# Generated by FakeRAM 2.0
VERSION 5.7 ;
BUSBITCHARS "[]" ;
PROPERTYDEFINITIONS
  MACRO width INTEGER ;
  MACRO depth INTEGER ;
  MACRO banks INTEGER ;
END PROPERTYDEFINITIONS
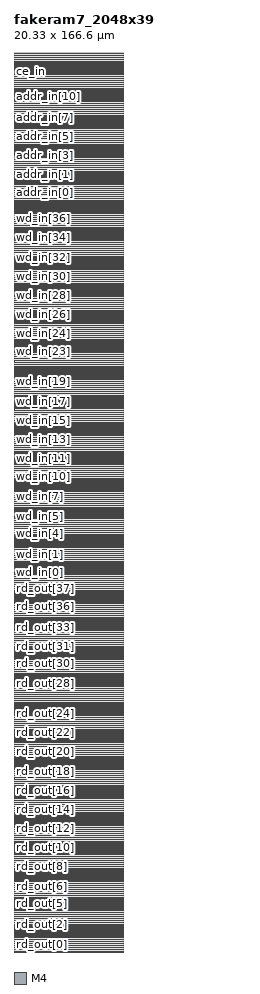
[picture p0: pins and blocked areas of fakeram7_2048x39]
MACRO fakeram7_2048x39
  PROPERTY width 39 ;
  PROPERTY depth 2048 ;
  PROPERTY banks 4 ;
  FOREIGN fakeram7_2048x39 0 0 ;
  SYMMETRY X Y R90 ;
  SIZE 20.330 BY 166.600 ;
  CLASS BLOCK ;
  PIN rd_out[0]
    DIRECTION OUTPUT ;
    USE SIGNAL ;
    SHAPE ABUTMENT ;
    PORT
      LAYER M4 ;
      RECT 0.000 0.048 0.024 0.072 ;
    END
  END rd_out[0]
  PIN rd_out[1]
    DIRECTION OUTPUT ;
    USE SIGNAL ;
    SHAPE ABUTMENT ;
    PORT
      LAYER M4 ;
      RECT 0.000 1.824 0.024 1.848 ;
    END
  END rd_out[1]
  PIN rd_out[2]
    DIRECTION OUTPUT ;
    USE SIGNAL ;
    SHAPE ABUTMENT ;
    PORT
      LAYER M4 ;
      RECT 0.000 3.600 0.024 3.624 ;
    END
  END rd_out[2]
  PIN rd_out[3]
    DIRECTION OUTPUT ;
    USE SIGNAL ;
    SHAPE ABUTMENT ;
    PORT
      LAYER M4 ;
      RECT 0.000 5.376 0.024 5.400 ;
    END
  END rd_out[3]
  PIN rd_out[4]
    DIRECTION OUTPUT ;
    USE SIGNAL ;
    SHAPE ABUTMENT ;
    PORT
      LAYER M4 ;
      RECT 0.000 7.152 0.024 7.176 ;
    END
  END rd_out[4]
  PIN rd_out[5]
    DIRECTION OUTPUT ;
    USE SIGNAL ;
    SHAPE ABUTMENT ;
    PORT
      LAYER M4 ;
      RECT 0.000 8.928 0.024 8.952 ;
    END
  END rd_out[5]
  PIN rd_out[6]
    DIRECTION OUTPUT ;
    USE SIGNAL ;
    SHAPE ABUTMENT ;
    PORT
      LAYER M4 ;
      RECT 0.000 10.704 0.024 10.728 ;
    END
  END rd_out[6]
  PIN rd_out[7]
    DIRECTION OUTPUT ;
    USE SIGNAL ;
    SHAPE ABUTMENT ;
    PORT
      LAYER M4 ;
      RECT 0.000 12.480 0.024 12.504 ;
    END
  END rd_out[7]
  PIN rd_out[8]
    DIRECTION OUTPUT ;
    USE SIGNAL ;
    SHAPE ABUTMENT ;
    PORT
      LAYER M4 ;
      RECT 0.000 14.256 0.024 14.280 ;
    END
  END rd_out[8]
  PIN rd_out[9]
    DIRECTION OUTPUT ;
    USE SIGNAL ;
    SHAPE ABUTMENT ;
    PORT
      LAYER M4 ;
      RECT 0.000 16.032 0.024 16.056 ;
    END
  END rd_out[9]
  PIN rd_out[10]
    DIRECTION OUTPUT ;
    USE SIGNAL ;
    SHAPE ABUTMENT ;
    PORT
      LAYER M4 ;
      RECT 0.000 17.808 0.024 17.832 ;
    END
  END rd_out[10]
  PIN rd_out[11]
    DIRECTION OUTPUT ;
    USE SIGNAL ;
    SHAPE ABUTMENT ;
    PORT
      LAYER M4 ;
      RECT 0.000 19.584 0.024 19.608 ;
    END
  END rd_out[11]
  PIN rd_out[12]
    DIRECTION OUTPUT ;
    USE SIGNAL ;
    SHAPE ABUTMENT ;
    PORT
      LAYER M4 ;
      RECT 0.000 21.360 0.024 21.384 ;
    END
  END rd_out[12]
  PIN rd_out[13]
    DIRECTION OUTPUT ;
    USE SIGNAL ;
    SHAPE ABUTMENT ;
    PORT
      LAYER M4 ;
      RECT 0.000 23.136 0.024 23.160 ;
    END
  END rd_out[13]
  PIN rd_out[14]
    DIRECTION OUTPUT ;
    USE SIGNAL ;
    SHAPE ABUTMENT ;
    PORT
      LAYER M4 ;
      RECT 0.000 24.912 0.024 24.936 ;
    END
  END rd_out[14]
  PIN rd_out[15]
    DIRECTION OUTPUT ;
    USE SIGNAL ;
    SHAPE ABUTMENT ;
    PORT
      LAYER M4 ;
      RECT 0.000 26.688 0.024 26.712 ;
    END
  END rd_out[15]
  PIN rd_out[16]
    DIRECTION OUTPUT ;
    USE SIGNAL ;
    SHAPE ABUTMENT ;
    PORT
      LAYER M4 ;
      RECT 0.000 28.464 0.024 28.488 ;
    END
  END rd_out[16]
  PIN rd_out[17]
    DIRECTION OUTPUT ;
    USE SIGNAL ;
    SHAPE ABUTMENT ;
    PORT
      LAYER M4 ;
      RECT 0.000 30.240 0.024 30.264 ;
    END
  END rd_out[17]
  PIN rd_out[18]
    DIRECTION OUTPUT ;
    USE SIGNAL ;
    SHAPE ABUTMENT ;
    PORT
      LAYER M4 ;
      RECT 0.000 32.016 0.024 32.040 ;
    END
  END rd_out[18]
  PIN rd_out[19]
    DIRECTION OUTPUT ;
    USE SIGNAL ;
    SHAPE ABUTMENT ;
    PORT
      LAYER M4 ;
      RECT 0.000 33.792 0.024 33.816 ;
    END
  END rd_out[19]
  PIN rd_out[20]
    DIRECTION OUTPUT ;
    USE SIGNAL ;
    SHAPE ABUTMENT ;
    PORT
      LAYER M4 ;
      RECT 0.000 35.568 0.024 35.592 ;
    END
  END rd_out[20]
  PIN rd_out[21]
    DIRECTION OUTPUT ;
    USE SIGNAL ;
    SHAPE ABUTMENT ;
    PORT
      LAYER M4 ;
      RECT 0.000 37.344 0.024 37.368 ;
    END
  END rd_out[21]
  PIN rd_out[22]
    DIRECTION OUTPUT ;
    USE SIGNAL ;
    SHAPE ABUTMENT ;
    PORT
      LAYER M4 ;
      RECT 0.000 39.120 0.024 39.144 ;
    END
  END rd_out[22]
  PIN rd_out[23]
    DIRECTION OUTPUT ;
    USE SIGNAL ;
    SHAPE ABUTMENT ;
    PORT
      LAYER M4 ;
      RECT 0.000 40.896 0.024 40.920 ;
    END
  END rd_out[23]
  PIN rd_out[24]
    DIRECTION OUTPUT ;
    USE SIGNAL ;
    SHAPE ABUTMENT ;
    PORT
      LAYER M4 ;
      RECT 0.000 42.672 0.024 42.696 ;
    END
  END rd_out[24]
  PIN rd_out[25]
    DIRECTION OUTPUT ;
    USE SIGNAL ;
    SHAPE ABUTMENT ;
    PORT
      LAYER M4 ;
      RECT 0.000 44.448 0.024 44.472 ;
    END
  END rd_out[25]
  PIN rd_out[26]
    DIRECTION OUTPUT ;
    USE SIGNAL ;
    SHAPE ABUTMENT ;
    PORT
      LAYER M4 ;
      RECT 0.000 46.224 0.024 46.248 ;
    END
  END rd_out[26]
  PIN rd_out[27]
    DIRECTION OUTPUT ;
    USE SIGNAL ;
    SHAPE ABUTMENT ;
    PORT
      LAYER M4 ;
      RECT 0.000 48.000 0.024 48.024 ;
    END
  END rd_out[27]
  PIN rd_out[28]
    DIRECTION OUTPUT ;
    USE SIGNAL ;
    SHAPE ABUTMENT ;
    PORT
      LAYER M4 ;
      RECT 0.000 49.776 0.024 49.800 ;
    END
  END rd_out[28]
  PIN rd_out[29]
    DIRECTION OUTPUT ;
    USE SIGNAL ;
    SHAPE ABUTMENT ;
    PORT
      LAYER M4 ;
      RECT 0.000 51.552 0.024 51.576 ;
    END
  END rd_out[29]
  PIN rd_out[30]
    DIRECTION OUTPUT ;
    USE SIGNAL ;
    SHAPE ABUTMENT ;
    PORT
      LAYER M4 ;
      RECT 0.000 53.328 0.024 53.352 ;
    END
  END rd_out[30]
  PIN rd_out[31]
    DIRECTION OUTPUT ;
    USE SIGNAL ;
    SHAPE ABUTMENT ;
    PORT
      LAYER M4 ;
      RECT 0.000 55.104 0.024 55.128 ;
    END
  END rd_out[31]
  PIN rd_out[32]
    DIRECTION OUTPUT ;
    USE SIGNAL ;
    SHAPE ABUTMENT ;
    PORT
      LAYER M4 ;
      RECT 0.000 56.880 0.024 56.904 ;
    END
  END rd_out[32]
  PIN rd_out[33]
    DIRECTION OUTPUT ;
    USE SIGNAL ;
    SHAPE ABUTMENT ;
    PORT
      LAYER M4 ;
      RECT 0.000 58.656 0.024 58.680 ;
    END
  END rd_out[33]
  PIN rd_out[34]
    DIRECTION OUTPUT ;
    USE SIGNAL ;
    SHAPE ABUTMENT ;
    PORT
      LAYER M4 ;
      RECT 0.000 60.432 0.024 60.456 ;
    END
  END rd_out[34]
  PIN rd_out[35]
    DIRECTION OUTPUT ;
    USE SIGNAL ;
    SHAPE ABUTMENT ;
    PORT
      LAYER M4 ;
      RECT 0.000 62.208 0.024 62.232 ;
    END
  END rd_out[35]
  PIN rd_out[36]
    DIRECTION OUTPUT ;
    USE SIGNAL ;
    SHAPE ABUTMENT ;
    PORT
      LAYER M4 ;
      RECT 0.000 63.984 0.024 64.008 ;
    END
  END rd_out[36]
  PIN rd_out[37]
    DIRECTION OUTPUT ;
    USE SIGNAL ;
    SHAPE ABUTMENT ;
    PORT
      LAYER M4 ;
      RECT 0.000 65.760 0.024 65.784 ;
    END
  END rd_out[37]
  PIN rd_out[38]
    DIRECTION OUTPUT ;
    USE SIGNAL ;
    SHAPE ABUTMENT ;
    PORT
      LAYER M4 ;
      RECT 0.000 67.536 0.024 67.560 ;
    END
  END rd_out[38]
  PIN wd_in[0]
    DIRECTION INPUT ;
    USE SIGNAL ;
    SHAPE ABUTMENT ;
    PORT
      LAYER M4 ;
      RECT 0.000 70.320 0.024 70.344 ;
    END
  END wd_in[0]
  PIN wd_in[1]
    DIRECTION INPUT ;
    USE SIGNAL ;
    SHAPE ABUTMENT ;
    PORT
      LAYER M4 ;
      RECT 0.000 72.096 0.024 72.120 ;
    END
  END wd_in[1]
  PIN wd_in[2]
    DIRECTION INPUT ;
    USE SIGNAL ;
    SHAPE ABUTMENT ;
    PORT
      LAYER M4 ;
      RECT 0.000 73.872 0.024 73.896 ;
    END
  END wd_in[2]
  PIN wd_in[3]
    DIRECTION INPUT ;
    USE SIGNAL ;
    SHAPE ABUTMENT ;
    PORT
      LAYER M4 ;
      RECT 0.000 75.648 0.024 75.672 ;
    END
  END wd_in[3]
  PIN wd_in[4]
    DIRECTION INPUT ;
    USE SIGNAL ;
    SHAPE ABUTMENT ;
    PORT
      LAYER M4 ;
      RECT 0.000 77.424 0.024 77.448 ;
    END
  END wd_in[4]
  PIN wd_in[5]
    DIRECTION INPUT ;
    USE SIGNAL ;
    SHAPE ABUTMENT ;
    PORT
      LAYER M4 ;
      RECT 0.000 79.200 0.024 79.224 ;
    END
  END wd_in[5]
  PIN wd_in[6]
    DIRECTION INPUT ;
    USE SIGNAL ;
    SHAPE ABUTMENT ;
    PORT
      LAYER M4 ;
      RECT 0.000 80.976 0.024 81.000 ;
    END
  END wd_in[6]
  PIN wd_in[7]
    DIRECTION INPUT ;
    USE SIGNAL ;
    SHAPE ABUTMENT ;
    PORT
      LAYER M4 ;
      RECT 0.000 82.752 0.024 82.776 ;
    END
  END wd_in[7]
  PIN wd_in[8]
    DIRECTION INPUT ;
    USE SIGNAL ;
    SHAPE ABUTMENT ;
    PORT
      LAYER M4 ;
      RECT 0.000 84.528 0.024 84.552 ;
    END
  END wd_in[8]
  PIN wd_in[9]
    DIRECTION INPUT ;
    USE SIGNAL ;
    SHAPE ABUTMENT ;
    PORT
      LAYER M4 ;
      RECT 0.000 86.304 0.024 86.328 ;
    END
  END wd_in[9]
  PIN wd_in[10]
    DIRECTION INPUT ;
    USE SIGNAL ;
    SHAPE ABUTMENT ;
    PORT
      LAYER M4 ;
      RECT 0.000 88.080 0.024 88.104 ;
    END
  END wd_in[10]
  PIN wd_in[11]
    DIRECTION INPUT ;
    USE SIGNAL ;
    SHAPE ABUTMENT ;
    PORT
      LAYER M4 ;
      RECT 0.000 89.856 0.024 89.880 ;
    END
  END wd_in[11]
  PIN wd_in[12]
    DIRECTION INPUT ;
    USE SIGNAL ;
    SHAPE ABUTMENT ;
    PORT
      LAYER M4 ;
      RECT 0.000 91.632 0.024 91.656 ;
    END
  END wd_in[12]
  PIN wd_in[13]
    DIRECTION INPUT ;
    USE SIGNAL ;
    SHAPE ABUTMENT ;
    PORT
      LAYER M4 ;
      RECT 0.000 93.408 0.024 93.432 ;
    END
  END wd_in[13]
  PIN wd_in[14]
    DIRECTION INPUT ;
    USE SIGNAL ;
    SHAPE ABUTMENT ;
    PORT
      LAYER M4 ;
      RECT 0.000 95.184 0.024 95.208 ;
    END
  END wd_in[14]
  PIN wd_in[15]
    DIRECTION INPUT ;
    USE SIGNAL ;
    SHAPE ABUTMENT ;
    PORT
      LAYER M4 ;
      RECT 0.000 96.960 0.024 96.984 ;
    END
  END wd_in[15]
  PIN wd_in[16]
    DIRECTION INPUT ;
    USE SIGNAL ;
    SHAPE ABUTMENT ;
    PORT
      LAYER M4 ;
      RECT 0.000 98.736 0.024 98.760 ;
    END
  END wd_in[16]
  PIN wd_in[17]
    DIRECTION INPUT ;
    USE SIGNAL ;
    SHAPE ABUTMENT ;
    PORT
      LAYER M4 ;
      RECT 0.000 100.512 0.024 100.536 ;
    END
  END wd_in[17]
  PIN wd_in[18]
    DIRECTION INPUT ;
    USE SIGNAL ;
    SHAPE ABUTMENT ;
    PORT
      LAYER M4 ;
      RECT 0.000 102.288 0.024 102.312 ;
    END
  END wd_in[18]
  PIN wd_in[19]
    DIRECTION INPUT ;
    USE SIGNAL ;
    SHAPE ABUTMENT ;
    PORT
      LAYER M4 ;
      RECT 0.000 104.064 0.024 104.088 ;
    END
  END wd_in[19]
  PIN wd_in[20]
    DIRECTION INPUT ;
    USE SIGNAL ;
    SHAPE ABUTMENT ;
    PORT
      LAYER M4 ;
      RECT 0.000 105.840 0.024 105.864 ;
    END
  END wd_in[20]
  PIN wd_in[21]
    DIRECTION INPUT ;
    USE SIGNAL ;
    SHAPE ABUTMENT ;
    PORT
      LAYER M4 ;
      RECT 0.000 107.616 0.024 107.640 ;
    END
  END wd_in[21]
  PIN wd_in[22]
    DIRECTION INPUT ;
    USE SIGNAL ;
    SHAPE ABUTMENT ;
    PORT
      LAYER M4 ;
      RECT 0.000 109.392 0.024 109.416 ;
    END
  END wd_in[22]
  PIN wd_in[23]
    DIRECTION INPUT ;
    USE SIGNAL ;
    SHAPE ABUTMENT ;
    PORT
      LAYER M4 ;
      RECT 0.000 111.168 0.024 111.192 ;
    END
  END wd_in[23]
  PIN wd_in[24]
    DIRECTION INPUT ;
    USE SIGNAL ;
    SHAPE ABUTMENT ;
    PORT
      LAYER M4 ;
      RECT 0.000 112.944 0.024 112.968 ;
    END
  END wd_in[24]
  PIN wd_in[25]
    DIRECTION INPUT ;
    USE SIGNAL ;
    SHAPE ABUTMENT ;
    PORT
      LAYER M4 ;
      RECT 0.000 114.720 0.024 114.744 ;
    END
  END wd_in[25]
  PIN wd_in[26]
    DIRECTION INPUT ;
    USE SIGNAL ;
    SHAPE ABUTMENT ;
    PORT
      LAYER M4 ;
      RECT 0.000 116.496 0.024 116.520 ;
    END
  END wd_in[26]
  PIN wd_in[27]
    DIRECTION INPUT ;
    USE SIGNAL ;
    SHAPE ABUTMENT ;
    PORT
      LAYER M4 ;
      RECT 0.000 118.272 0.024 118.296 ;
    END
  END wd_in[27]
  PIN wd_in[28]
    DIRECTION INPUT ;
    USE SIGNAL ;
    SHAPE ABUTMENT ;
    PORT
      LAYER M4 ;
      RECT 0.000 120.048 0.024 120.072 ;
    END
  END wd_in[28]
  PIN wd_in[29]
    DIRECTION INPUT ;
    USE SIGNAL ;
    SHAPE ABUTMENT ;
    PORT
      LAYER M4 ;
      RECT 0.000 121.824 0.024 121.848 ;
    END
  END wd_in[29]
  PIN wd_in[30]
    DIRECTION INPUT ;
    USE SIGNAL ;
    SHAPE ABUTMENT ;
    PORT
      LAYER M4 ;
      RECT 0.000 123.600 0.024 123.624 ;
    END
  END wd_in[30]
  PIN wd_in[31]
    DIRECTION INPUT ;
    USE SIGNAL ;
    SHAPE ABUTMENT ;
    PORT
      LAYER M4 ;
      RECT 0.000 125.376 0.024 125.400 ;
    END
  END wd_in[31]
  PIN wd_in[32]
    DIRECTION INPUT ;
    USE SIGNAL ;
    SHAPE ABUTMENT ;
    PORT
      LAYER M4 ;
      RECT 0.000 127.152 0.024 127.176 ;
    END
  END wd_in[32]
  PIN wd_in[33]
    DIRECTION INPUT ;
    USE SIGNAL ;
    SHAPE ABUTMENT ;
    PORT
      LAYER M4 ;
      RECT 0.000 128.928 0.024 128.952 ;
    END
  END wd_in[33]
  PIN wd_in[34]
    DIRECTION INPUT ;
    USE SIGNAL ;
    SHAPE ABUTMENT ;
    PORT
      LAYER M4 ;
      RECT 0.000 130.704 0.024 130.728 ;
    END
  END wd_in[34]
  PIN wd_in[35]
    DIRECTION INPUT ;
    USE SIGNAL ;
    SHAPE ABUTMENT ;
    PORT
      LAYER M4 ;
      RECT 0.000 132.480 0.024 132.504 ;
    END
  END wd_in[35]
  PIN wd_in[36]
    DIRECTION INPUT ;
    USE SIGNAL ;
    SHAPE ABUTMENT ;
    PORT
      LAYER M4 ;
      RECT 0.000 134.256 0.024 134.280 ;
    END
  END wd_in[36]
  PIN wd_in[37]
    DIRECTION INPUT ;
    USE SIGNAL ;
    SHAPE ABUTMENT ;
    PORT
      LAYER M4 ;
      RECT 0.000 136.032 0.024 136.056 ;
    END
  END wd_in[37]
  PIN wd_in[38]
    DIRECTION INPUT ;
    USE SIGNAL ;
    SHAPE ABUTMENT ;
    PORT
      LAYER M4 ;
      RECT 0.000 137.808 0.024 137.832 ;
    END
  END wd_in[38]
  PIN addr_in[0]
    DIRECTION INPUT ;
    USE SIGNAL ;
    SHAPE ABUTMENT ;
    PORT
      LAYER M4 ;
      RECT 0.000 140.592 0.024 140.616 ;
    END
  END addr_in[0]
  PIN addr_in[1]
    DIRECTION INPUT ;
    USE SIGNAL ;
    SHAPE ABUTMENT ;
    PORT
      LAYER M4 ;
      RECT 0.000 142.368 0.024 142.392 ;
    END
  END addr_in[1]
  PIN addr_in[2]
    DIRECTION INPUT ;
    USE SIGNAL ;
    SHAPE ABUTMENT ;
    PORT
      LAYER M4 ;
      RECT 0.000 144.144 0.024 144.168 ;
    END
  END addr_in[2]
  PIN addr_in[3]
    DIRECTION INPUT ;
    USE SIGNAL ;
    SHAPE ABUTMENT ;
    PORT
      LAYER M4 ;
      RECT 0.000 145.920 0.024 145.944 ;
    END
  END addr_in[3]
  PIN addr_in[4]
    DIRECTION INPUT ;
    USE SIGNAL ;
    SHAPE ABUTMENT ;
    PORT
      LAYER M4 ;
      RECT 0.000 147.696 0.024 147.720 ;
    END
  END addr_in[4]
  PIN addr_in[5]
    DIRECTION INPUT ;
    USE SIGNAL ;
    SHAPE ABUTMENT ;
    PORT
      LAYER M4 ;
      RECT 0.000 149.472 0.024 149.496 ;
    END
  END addr_in[5]
  PIN addr_in[6]
    DIRECTION INPUT ;
    USE SIGNAL ;
    SHAPE ABUTMENT ;
    PORT
      LAYER M4 ;
      RECT 0.000 151.248 0.024 151.272 ;
    END
  END addr_in[6]
  PIN addr_in[7]
    DIRECTION INPUT ;
    USE SIGNAL ;
    SHAPE ABUTMENT ;
    PORT
      LAYER M4 ;
      RECT 0.000 153.024 0.024 153.048 ;
    END
  END addr_in[7]
  PIN addr_in[8]
    DIRECTION INPUT ;
    USE SIGNAL ;
    SHAPE ABUTMENT ;
    PORT
      LAYER M4 ;
      RECT 0.000 154.800 0.024 154.824 ;
    END
  END addr_in[8]
  PIN addr_in[9]
    DIRECTION INPUT ;
    USE SIGNAL ;
    SHAPE ABUTMENT ;
    PORT
      LAYER M4 ;
      RECT 0.000 156.576 0.024 156.600 ;
    END
  END addr_in[9]
  PIN addr_in[10]
    DIRECTION INPUT ;
    USE SIGNAL ;
    SHAPE ABUTMENT ;
    PORT
      LAYER M4 ;
      RECT 0.000 158.352 0.024 158.376 ;
    END
  END addr_in[10]
  PIN we_in
    DIRECTION INPUT ;
    USE SIGNAL ;
    SHAPE ABUTMENT ;
    PORT
      LAYER M4 ;
      RECT 0.000 161.136 0.024 161.160 ;
    END
  END we_in
  PIN ce_in
    DIRECTION INPUT ;
    USE SIGNAL ;
    SHAPE ABUTMENT ;
    PORT
      LAYER M4 ;
      RECT 0.000 162.912 0.024 162.936 ;
    END
  END ce_in
  PIN clk
    DIRECTION INPUT ;
    USE SIGNAL ;
    SHAPE ABUTMENT ;
    PORT
      LAYER M4 ;
      RECT 0.000 164.688 0.024 164.712 ;
    END
  END clk
  PIN VSS
    DIRECTION INOUT ;
    USE GROUND ;
    PORT
      LAYER M4 ;
      RECT 0.048 0.000 20.282 0.096 ;
      RECT 0.048 0.768 20.282 0.864 ;
      RECT 0.048 1.536 20.282 1.632 ;
      RECT 0.048 2.304 20.282 2.400 ;
      RECT 0.048 3.072 20.282 3.168 ;
      RECT 0.048 3.840 20.282 3.936 ;
      RECT 0.048 4.608 20.282 4.704 ;
      RECT 0.048 5.376 20.282 5.472 ;
      RECT 0.048 6.144 20.282 6.240 ;
      RECT 0.048 6.912 20.282 7.008 ;
      RECT 0.048 7.680 20.282 7.776 ;
      RECT 0.048 8.448 20.282 8.544 ;
      RECT 0.048 9.216 20.282 9.312 ;
      RECT 0.048 9.984 20.282 10.080 ;
      RECT 0.048 10.752 20.282 10.848 ;
      RECT 0.048 11.520 20.282 11.616 ;
      RECT 0.048 12.288 20.282 12.384 ;
      RECT 0.048 13.056 20.282 13.152 ;
      RECT 0.048 13.824 20.282 13.920 ;
      RECT 0.048 14.592 20.282 14.688 ;
      RECT 0.048 15.360 20.282 15.456 ;
      RECT 0.048 16.128 20.282 16.224 ;
      RECT 0.048 16.896 20.282 16.992 ;
      RECT 0.048 17.664 20.282 17.760 ;
      RECT 0.048 18.432 20.282 18.528 ;
      RECT 0.048 19.200 20.282 19.296 ;
      RECT 0.048 19.968 20.282 20.064 ;
      RECT 0.048 20.736 20.282 20.832 ;
      RECT 0.048 21.504 20.282 21.600 ;
      RECT 0.048 22.272 20.282 22.368 ;
      RECT 0.048 23.040 20.282 23.136 ;
      RECT 0.048 23.808 20.282 23.904 ;
      RECT 0.048 24.576 20.282 24.672 ;
      RECT 0.048 25.344 20.282 25.440 ;
      RECT 0.048 26.112 20.282 26.208 ;
      RECT 0.048 26.880 20.282 26.976 ;
      RECT 0.048 27.648 20.282 27.744 ;
      RECT 0.048 28.416 20.282 28.512 ;
      RECT 0.048 29.184 20.282 29.280 ;
      RECT 0.048 29.952 20.282 30.048 ;
      RECT 0.048 30.720 20.282 30.816 ;
      RECT 0.048 31.488 20.282 31.584 ;
      RECT 0.048 32.256 20.282 32.352 ;
      RECT 0.048 33.024 20.282 33.120 ;
      RECT 0.048 33.792 20.282 33.888 ;
      RECT 0.048 34.560 20.282 34.656 ;
      RECT 0.048 35.328 20.282 35.424 ;
      RECT 0.048 36.096 20.282 36.192 ;
      RECT 0.048 36.864 20.282 36.960 ;
      RECT 0.048 37.632 20.282 37.728 ;
      RECT 0.048 38.400 20.282 38.496 ;
      RECT 0.048 39.168 20.282 39.264 ;
      RECT 0.048 39.936 20.282 40.032 ;
      RECT 0.048 40.704 20.282 40.800 ;
      RECT 0.048 41.472 20.282 41.568 ;
      RECT 0.048 42.240 20.282 42.336 ;
      RECT 0.048 43.008 20.282 43.104 ;
      RECT 0.048 43.776 20.282 43.872 ;
      RECT 0.048 44.544 20.282 44.640 ;
      RECT 0.048 45.312 20.282 45.408 ;
      RECT 0.048 46.080 20.282 46.176 ;
      RECT 0.048 46.848 20.282 46.944 ;
      RECT 0.048 47.616 20.282 47.712 ;
      RECT 0.048 48.384 20.282 48.480 ;
      RECT 0.048 49.152 20.282 49.248 ;
      RECT 0.048 49.920 20.282 50.016 ;
      RECT 0.048 50.688 20.282 50.784 ;
      RECT 0.048 51.456 20.282 51.552 ;
      RECT 0.048 52.224 20.282 52.320 ;
      RECT 0.048 52.992 20.282 53.088 ;
      RECT 0.048 53.760 20.282 53.856 ;
      RECT 0.048 54.528 20.282 54.624 ;
      RECT 0.048 55.296 20.282 55.392 ;
      RECT 0.048 56.064 20.282 56.160 ;
      RECT 0.048 56.832 20.282 56.928 ;
      RECT 0.048 57.600 20.282 57.696 ;
      RECT 0.048 58.368 20.282 58.464 ;
      RECT 0.048 59.136 20.282 59.232 ;
      RECT 0.048 59.904 20.282 60.000 ;
      RECT 0.048 60.672 20.282 60.768 ;
      RECT 0.048 61.440 20.282 61.536 ;
      RECT 0.048 62.208 20.282 62.304 ;
      RECT 0.048 62.976 20.282 63.072 ;
      RECT 0.048 63.744 20.282 63.840 ;
      RECT 0.048 64.512 20.282 64.608 ;
      RECT 0.048 65.280 20.282 65.376 ;
      RECT 0.048 66.048 20.282 66.144 ;
      RECT 0.048 66.816 20.282 66.912 ;
      RECT 0.048 67.584 20.282 67.680 ;
      RECT 0.048 68.352 20.282 68.448 ;
      RECT 0.048 69.120 20.282 69.216 ;
      RECT 0.048 69.888 20.282 69.984 ;
      RECT 0.048 70.656 20.282 70.752 ;
      RECT 0.048 71.424 20.282 71.520 ;
      RECT 0.048 72.192 20.282 72.288 ;
      RECT 0.048 72.960 20.282 73.056 ;
      RECT 0.048 73.728 20.282 73.824 ;
      RECT 0.048 74.496 20.282 74.592 ;
      RECT 0.048 75.264 20.282 75.360 ;
      RECT 0.048 76.032 20.282 76.128 ;
      RECT 0.048 76.800 20.282 76.896 ;
      RECT 0.048 77.568 20.282 77.664 ;
      RECT 0.048 78.336 20.282 78.432 ;
      RECT 0.048 79.104 20.282 79.200 ;
      RECT 0.048 79.872 20.282 79.968 ;
      RECT 0.048 80.640 20.282 80.736 ;
      RECT 0.048 81.408 20.282 81.504 ;
      RECT 0.048 82.176 20.282 82.272 ;
      RECT 0.048 82.944 20.282 83.040 ;
      RECT 0.048 83.712 20.282 83.808 ;
      RECT 0.048 84.480 20.282 84.576 ;
      RECT 0.048 85.248 20.282 85.344 ;
      RECT 0.048 86.016 20.282 86.112 ;
      RECT 0.048 86.784 20.282 86.880 ;
      RECT 0.048 87.552 20.282 87.648 ;
      RECT 0.048 88.320 20.282 88.416 ;
      RECT 0.048 89.088 20.282 89.184 ;
      RECT 0.048 89.856 20.282 89.952 ;
      RECT 0.048 90.624 20.282 90.720 ;
      RECT 0.048 91.392 20.282 91.488 ;
      RECT 0.048 92.160 20.282 92.256 ;
      RECT 0.048 92.928 20.282 93.024 ;
      RECT 0.048 93.696 20.282 93.792 ;
      RECT 0.048 94.464 20.282 94.560 ;
      RECT 0.048 95.232 20.282 95.328 ;
      RECT 0.048 96.000 20.282 96.096 ;
      RECT 0.048 96.768 20.282 96.864 ;
      RECT 0.048 97.536 20.282 97.632 ;
      RECT 0.048 98.304 20.282 98.400 ;
      RECT 0.048 99.072 20.282 99.168 ;
      RECT 0.048 99.840 20.282 99.936 ;
      RECT 0.048 100.608 20.282 100.704 ;
      RECT 0.048 101.376 20.282 101.472 ;
      RECT 0.048 102.144 20.282 102.240 ;
      RECT 0.048 102.912 20.282 103.008 ;
      RECT 0.048 103.680 20.282 103.776 ;
      RECT 0.048 104.448 20.282 104.544 ;
      RECT 0.048 105.216 20.282 105.312 ;
      RECT 0.048 105.984 20.282 106.080 ;
      RECT 0.048 106.752 20.282 106.848 ;
      RECT 0.048 107.520 20.282 107.616 ;
      RECT 0.048 108.288 20.282 108.384 ;
      RECT 0.048 109.056 20.282 109.152 ;
      RECT 0.048 109.824 20.282 109.920 ;
      RECT 0.048 110.592 20.282 110.688 ;
      RECT 0.048 111.360 20.282 111.456 ;
      RECT 0.048 112.128 20.282 112.224 ;
      RECT 0.048 112.896 20.282 112.992 ;
      RECT 0.048 113.664 20.282 113.760 ;
      RECT 0.048 114.432 20.282 114.528 ;
      RECT 0.048 115.200 20.282 115.296 ;
      RECT 0.048 115.968 20.282 116.064 ;
      RECT 0.048 116.736 20.282 116.832 ;
      RECT 0.048 117.504 20.282 117.600 ;
      RECT 0.048 118.272 20.282 118.368 ;
      RECT 0.048 119.040 20.282 119.136 ;
      RECT 0.048 119.808 20.282 119.904 ;
      RECT 0.048 120.576 20.282 120.672 ;
      RECT 0.048 121.344 20.282 121.440 ;
      RECT 0.048 122.112 20.282 122.208 ;
      RECT 0.048 122.880 20.282 122.976 ;
      RECT 0.048 123.648 20.282 123.744 ;
      RECT 0.048 124.416 20.282 124.512 ;
      RECT 0.048 125.184 20.282 125.280 ;
      RECT 0.048 125.952 20.282 126.048 ;
      RECT 0.048 126.720 20.282 126.816 ;
      RECT 0.048 127.488 20.282 127.584 ;
      RECT 0.048 128.256 20.282 128.352 ;
      RECT 0.048 129.024 20.282 129.120 ;
      RECT 0.048 129.792 20.282 129.888 ;
      RECT 0.048 130.560 20.282 130.656 ;
      RECT 0.048 131.328 20.282 131.424 ;
      RECT 0.048 132.096 20.282 132.192 ;
      RECT 0.048 132.864 20.282 132.960 ;
      RECT 0.048 133.632 20.282 133.728 ;
      RECT 0.048 134.400 20.282 134.496 ;
      RECT 0.048 135.168 20.282 135.264 ;
      RECT 0.048 135.936 20.282 136.032 ;
      RECT 0.048 136.704 20.282 136.800 ;
      RECT 0.048 137.472 20.282 137.568 ;
      RECT 0.048 138.240 20.282 138.336 ;
      RECT 0.048 139.008 20.282 139.104 ;
      RECT 0.048 139.776 20.282 139.872 ;
      RECT 0.048 140.544 20.282 140.640 ;
      RECT 0.048 141.312 20.282 141.408 ;
      RECT 0.048 142.080 20.282 142.176 ;
      RECT 0.048 142.848 20.282 142.944 ;
      RECT 0.048 143.616 20.282 143.712 ;
      RECT 0.048 144.384 20.282 144.480 ;
      RECT 0.048 145.152 20.282 145.248 ;
      RECT 0.048 145.920 20.282 146.016 ;
      RECT 0.048 146.688 20.282 146.784 ;
      RECT 0.048 147.456 20.282 147.552 ;
      RECT 0.048 148.224 20.282 148.320 ;
      RECT 0.048 148.992 20.282 149.088 ;
      RECT 0.048 149.760 20.282 149.856 ;
      RECT 0.048 150.528 20.282 150.624 ;
      RECT 0.048 151.296 20.282 151.392 ;
      RECT 0.048 152.064 20.282 152.160 ;
      RECT 0.048 152.832 20.282 152.928 ;
      RECT 0.048 153.600 20.282 153.696 ;
      RECT 0.048 154.368 20.282 154.464 ;
      RECT 0.048 155.136 20.282 155.232 ;
      RECT 0.048 155.904 20.282 156.000 ;
      RECT 0.048 156.672 20.282 156.768 ;
      RECT 0.048 157.440 20.282 157.536 ;
      RECT 0.048 158.208 20.282 158.304 ;
      RECT 0.048 158.976 20.282 159.072 ;
      RECT 0.048 159.744 20.282 159.840 ;
      RECT 0.048 160.512 20.282 160.608 ;
      RECT 0.048 161.280 20.282 161.376 ;
      RECT 0.048 162.048 20.282 162.144 ;
      RECT 0.048 162.816 20.282 162.912 ;
      RECT 0.048 163.584 20.282 163.680 ;
      RECT 0.048 164.352 20.282 164.448 ;
      RECT 0.048 165.120 20.282 165.216 ;
      RECT 0.048 165.888 20.282 165.984 ;
    END
  END VSS
  PIN VDD
    DIRECTION INOUT ;
    USE POWER ;
    PORT
      LAYER M4 ;
      RECT 0.048 0.384 20.282 0.480 ;
      RECT 0.048 1.152 20.282 1.248 ;
      RECT 0.048 1.920 20.282 2.016 ;
      RECT 0.048 2.688 20.282 2.784 ;
      RECT 0.048 3.456 20.282 3.552 ;
      RECT 0.048 4.224 20.282 4.320 ;
      RECT 0.048 4.992 20.282 5.088 ;
      RECT 0.048 5.760 20.282 5.856 ;
      RECT 0.048 6.528 20.282 6.624 ;
      RECT 0.048 7.296 20.282 7.392 ;
      RECT 0.048 8.064 20.282 8.160 ;
      RECT 0.048 8.832 20.282 8.928 ;
      RECT 0.048 9.600 20.282 9.696 ;
      RECT 0.048 10.368 20.282 10.464 ;
      RECT 0.048 11.136 20.282 11.232 ;
      RECT 0.048 11.904 20.282 12.000 ;
      RECT 0.048 12.672 20.282 12.768 ;
      RECT 0.048 13.440 20.282 13.536 ;
      RECT 0.048 14.208 20.282 14.304 ;
      RECT 0.048 14.976 20.282 15.072 ;
      RECT 0.048 15.744 20.282 15.840 ;
      RECT 0.048 16.512 20.282 16.608 ;
      RECT 0.048 17.280 20.282 17.376 ;
      RECT 0.048 18.048 20.282 18.144 ;
      RECT 0.048 18.816 20.282 18.912 ;
      RECT 0.048 19.584 20.282 19.680 ;
      RECT 0.048 20.352 20.282 20.448 ;
      RECT 0.048 21.120 20.282 21.216 ;
      RECT 0.048 21.888 20.282 21.984 ;
      RECT 0.048 22.656 20.282 22.752 ;
      RECT 0.048 23.424 20.282 23.520 ;
      RECT 0.048 24.192 20.282 24.288 ;
      RECT 0.048 24.960 20.282 25.056 ;
      RECT 0.048 25.728 20.282 25.824 ;
      RECT 0.048 26.496 20.282 26.592 ;
      RECT 0.048 27.264 20.282 27.360 ;
      RECT 0.048 28.032 20.282 28.128 ;
      RECT 0.048 28.800 20.282 28.896 ;
      RECT 0.048 29.568 20.282 29.664 ;
      RECT 0.048 30.336 20.282 30.432 ;
      RECT 0.048 31.104 20.282 31.200 ;
      RECT 0.048 31.872 20.282 31.968 ;
      RECT 0.048 32.640 20.282 32.736 ;
      RECT 0.048 33.408 20.282 33.504 ;
      RECT 0.048 34.176 20.282 34.272 ;
      RECT 0.048 34.944 20.282 35.040 ;
      RECT 0.048 35.712 20.282 35.808 ;
      RECT 0.048 36.480 20.282 36.576 ;
      RECT 0.048 37.248 20.282 37.344 ;
      RECT 0.048 38.016 20.282 38.112 ;
      RECT 0.048 38.784 20.282 38.880 ;
      RECT 0.048 39.552 20.282 39.648 ;
      RECT 0.048 40.320 20.282 40.416 ;
      RECT 0.048 41.088 20.282 41.184 ;
      RECT 0.048 41.856 20.282 41.952 ;
      RECT 0.048 42.624 20.282 42.720 ;
      RECT 0.048 43.392 20.282 43.488 ;
      RECT 0.048 44.160 20.282 44.256 ;
      RECT 0.048 44.928 20.282 45.024 ;
      RECT 0.048 45.696 20.282 45.792 ;
      RECT 0.048 46.464 20.282 46.560 ;
      RECT 0.048 47.232 20.282 47.328 ;
      RECT 0.048 48.000 20.282 48.096 ;
      RECT 0.048 48.768 20.282 48.864 ;
      RECT 0.048 49.536 20.282 49.632 ;
      RECT 0.048 50.304 20.282 50.400 ;
      RECT 0.048 51.072 20.282 51.168 ;
      RECT 0.048 51.840 20.282 51.936 ;
      RECT 0.048 52.608 20.282 52.704 ;
      RECT 0.048 53.376 20.282 53.472 ;
      RECT 0.048 54.144 20.282 54.240 ;
      RECT 0.048 54.912 20.282 55.008 ;
      RECT 0.048 55.680 20.282 55.776 ;
      RECT 0.048 56.448 20.282 56.544 ;
      RECT 0.048 57.216 20.282 57.312 ;
      RECT 0.048 57.984 20.282 58.080 ;
      RECT 0.048 58.752 20.282 58.848 ;
      RECT 0.048 59.520 20.282 59.616 ;
      RECT 0.048 60.288 20.282 60.384 ;
      RECT 0.048 61.056 20.282 61.152 ;
      RECT 0.048 61.824 20.282 61.920 ;
      RECT 0.048 62.592 20.282 62.688 ;
      RECT 0.048 63.360 20.282 63.456 ;
      RECT 0.048 64.128 20.282 64.224 ;
      RECT 0.048 64.896 20.282 64.992 ;
      RECT 0.048 65.664 20.282 65.760 ;
      RECT 0.048 66.432 20.282 66.528 ;
      RECT 0.048 67.200 20.282 67.296 ;
      RECT 0.048 67.968 20.282 68.064 ;
      RECT 0.048 68.736 20.282 68.832 ;
      RECT 0.048 69.504 20.282 69.600 ;
      RECT 0.048 70.272 20.282 70.368 ;
      RECT 0.048 71.040 20.282 71.136 ;
      RECT 0.048 71.808 20.282 71.904 ;
      RECT 0.048 72.576 20.282 72.672 ;
      RECT 0.048 73.344 20.282 73.440 ;
      RECT 0.048 74.112 20.282 74.208 ;
      RECT 0.048 74.880 20.282 74.976 ;
      RECT 0.048 75.648 20.282 75.744 ;
      RECT 0.048 76.416 20.282 76.512 ;
      RECT 0.048 77.184 20.282 77.280 ;
      RECT 0.048 77.952 20.282 78.048 ;
      RECT 0.048 78.720 20.282 78.816 ;
      RECT 0.048 79.488 20.282 79.584 ;
      RECT 0.048 80.256 20.282 80.352 ;
      RECT 0.048 81.024 20.282 81.120 ;
      RECT 0.048 81.792 20.282 81.888 ;
      RECT 0.048 82.560 20.282 82.656 ;
      RECT 0.048 83.328 20.282 83.424 ;
      RECT 0.048 84.096 20.282 84.192 ;
      RECT 0.048 84.864 20.282 84.960 ;
      RECT 0.048 85.632 20.282 85.728 ;
      RECT 0.048 86.400 20.282 86.496 ;
      RECT 0.048 87.168 20.282 87.264 ;
      RECT 0.048 87.936 20.282 88.032 ;
      RECT 0.048 88.704 20.282 88.800 ;
      RECT 0.048 89.472 20.282 89.568 ;
      RECT 0.048 90.240 20.282 90.336 ;
      RECT 0.048 91.008 20.282 91.104 ;
      RECT 0.048 91.776 20.282 91.872 ;
      RECT 0.048 92.544 20.282 92.640 ;
      RECT 0.048 93.312 20.282 93.408 ;
      RECT 0.048 94.080 20.282 94.176 ;
      RECT 0.048 94.848 20.282 94.944 ;
      RECT 0.048 95.616 20.282 95.712 ;
      RECT 0.048 96.384 20.282 96.480 ;
      RECT 0.048 97.152 20.282 97.248 ;
      RECT 0.048 97.920 20.282 98.016 ;
      RECT 0.048 98.688 20.282 98.784 ;
      RECT 0.048 99.456 20.282 99.552 ;
      RECT 0.048 100.224 20.282 100.320 ;
      RECT 0.048 100.992 20.282 101.088 ;
      RECT 0.048 101.760 20.282 101.856 ;
      RECT 0.048 102.528 20.282 102.624 ;
      RECT 0.048 103.296 20.282 103.392 ;
      RECT 0.048 104.064 20.282 104.160 ;
      RECT 0.048 104.832 20.282 104.928 ;
      RECT 0.048 105.600 20.282 105.696 ;
      RECT 0.048 106.368 20.282 106.464 ;
      RECT 0.048 107.136 20.282 107.232 ;
      RECT 0.048 107.904 20.282 108.000 ;
      RECT 0.048 108.672 20.282 108.768 ;
      RECT 0.048 109.440 20.282 109.536 ;
      RECT 0.048 110.208 20.282 110.304 ;
      RECT 0.048 110.976 20.282 111.072 ;
      RECT 0.048 111.744 20.282 111.840 ;
      RECT 0.048 112.512 20.282 112.608 ;
      RECT 0.048 113.280 20.282 113.376 ;
      RECT 0.048 114.048 20.282 114.144 ;
      RECT 0.048 114.816 20.282 114.912 ;
      RECT 0.048 115.584 20.282 115.680 ;
      RECT 0.048 116.352 20.282 116.448 ;
      RECT 0.048 117.120 20.282 117.216 ;
      RECT 0.048 117.888 20.282 117.984 ;
      RECT 0.048 118.656 20.282 118.752 ;
      RECT 0.048 119.424 20.282 119.520 ;
      RECT 0.048 120.192 20.282 120.288 ;
      RECT 0.048 120.960 20.282 121.056 ;
      RECT 0.048 121.728 20.282 121.824 ;
      RECT 0.048 122.496 20.282 122.592 ;
      RECT 0.048 123.264 20.282 123.360 ;
      RECT 0.048 124.032 20.282 124.128 ;
      RECT 0.048 124.800 20.282 124.896 ;
      RECT 0.048 125.568 20.282 125.664 ;
      RECT 0.048 126.336 20.282 126.432 ;
      RECT 0.048 127.104 20.282 127.200 ;
      RECT 0.048 127.872 20.282 127.968 ;
      RECT 0.048 128.640 20.282 128.736 ;
      RECT 0.048 129.408 20.282 129.504 ;
      RECT 0.048 130.176 20.282 130.272 ;
      RECT 0.048 130.944 20.282 131.040 ;
      RECT 0.048 131.712 20.282 131.808 ;
      RECT 0.048 132.480 20.282 132.576 ;
      RECT 0.048 133.248 20.282 133.344 ;
      RECT 0.048 134.016 20.282 134.112 ;
      RECT 0.048 134.784 20.282 134.880 ;
      RECT 0.048 135.552 20.282 135.648 ;
      RECT 0.048 136.320 20.282 136.416 ;
      RECT 0.048 137.088 20.282 137.184 ;
      RECT 0.048 137.856 20.282 137.952 ;
      RECT 0.048 138.624 20.282 138.720 ;
      RECT 0.048 139.392 20.282 139.488 ;
      RECT 0.048 140.160 20.282 140.256 ;
      RECT 0.048 140.928 20.282 141.024 ;
      RECT 0.048 141.696 20.282 141.792 ;
      RECT 0.048 142.464 20.282 142.560 ;
      RECT 0.048 143.232 20.282 143.328 ;
      RECT 0.048 144.000 20.282 144.096 ;
      RECT 0.048 144.768 20.282 144.864 ;
      RECT 0.048 145.536 20.282 145.632 ;
      RECT 0.048 146.304 20.282 146.400 ;
      RECT 0.048 147.072 20.282 147.168 ;
      RECT 0.048 147.840 20.282 147.936 ;
      RECT 0.048 148.608 20.282 148.704 ;
      RECT 0.048 149.376 20.282 149.472 ;
      RECT 0.048 150.144 20.282 150.240 ;
      RECT 0.048 150.912 20.282 151.008 ;
      RECT 0.048 151.680 20.282 151.776 ;
      RECT 0.048 152.448 20.282 152.544 ;
      RECT 0.048 153.216 20.282 153.312 ;
      RECT 0.048 153.984 20.282 154.080 ;
      RECT 0.048 154.752 20.282 154.848 ;
      RECT 0.048 155.520 20.282 155.616 ;
      RECT 0.048 156.288 20.282 156.384 ;
      RECT 0.048 157.056 20.282 157.152 ;
      RECT 0.048 157.824 20.282 157.920 ;
      RECT 0.048 158.592 20.282 158.688 ;
      RECT 0.048 159.360 20.282 159.456 ;
      RECT 0.048 160.128 20.282 160.224 ;
      RECT 0.048 160.896 20.282 160.992 ;
      RECT 0.048 161.664 20.282 161.760 ;
      RECT 0.048 162.432 20.282 162.528 ;
      RECT 0.048 163.200 20.282 163.296 ;
      RECT 0.048 163.968 20.282 164.064 ;
      RECT 0.048 164.736 20.282 164.832 ;
      RECT 0.048 165.504 20.282 165.600 ;
      RECT 0.048 166.272 20.282 166.368 ;
    END
  END VDD
  OBS
    LAYER M1 ;
    RECT 0 0 20.330 166.600 ;
    LAYER M2 ;
    RECT 0 0 20.330 166.600 ;
    LAYER M3 ;
    RECT 0 0 20.330 166.600 ;
    LAYER M4 ;
    RECT 0 0 20.330 166.600 ;
  END
END fakeram7_2048x39

END LIBRARY
